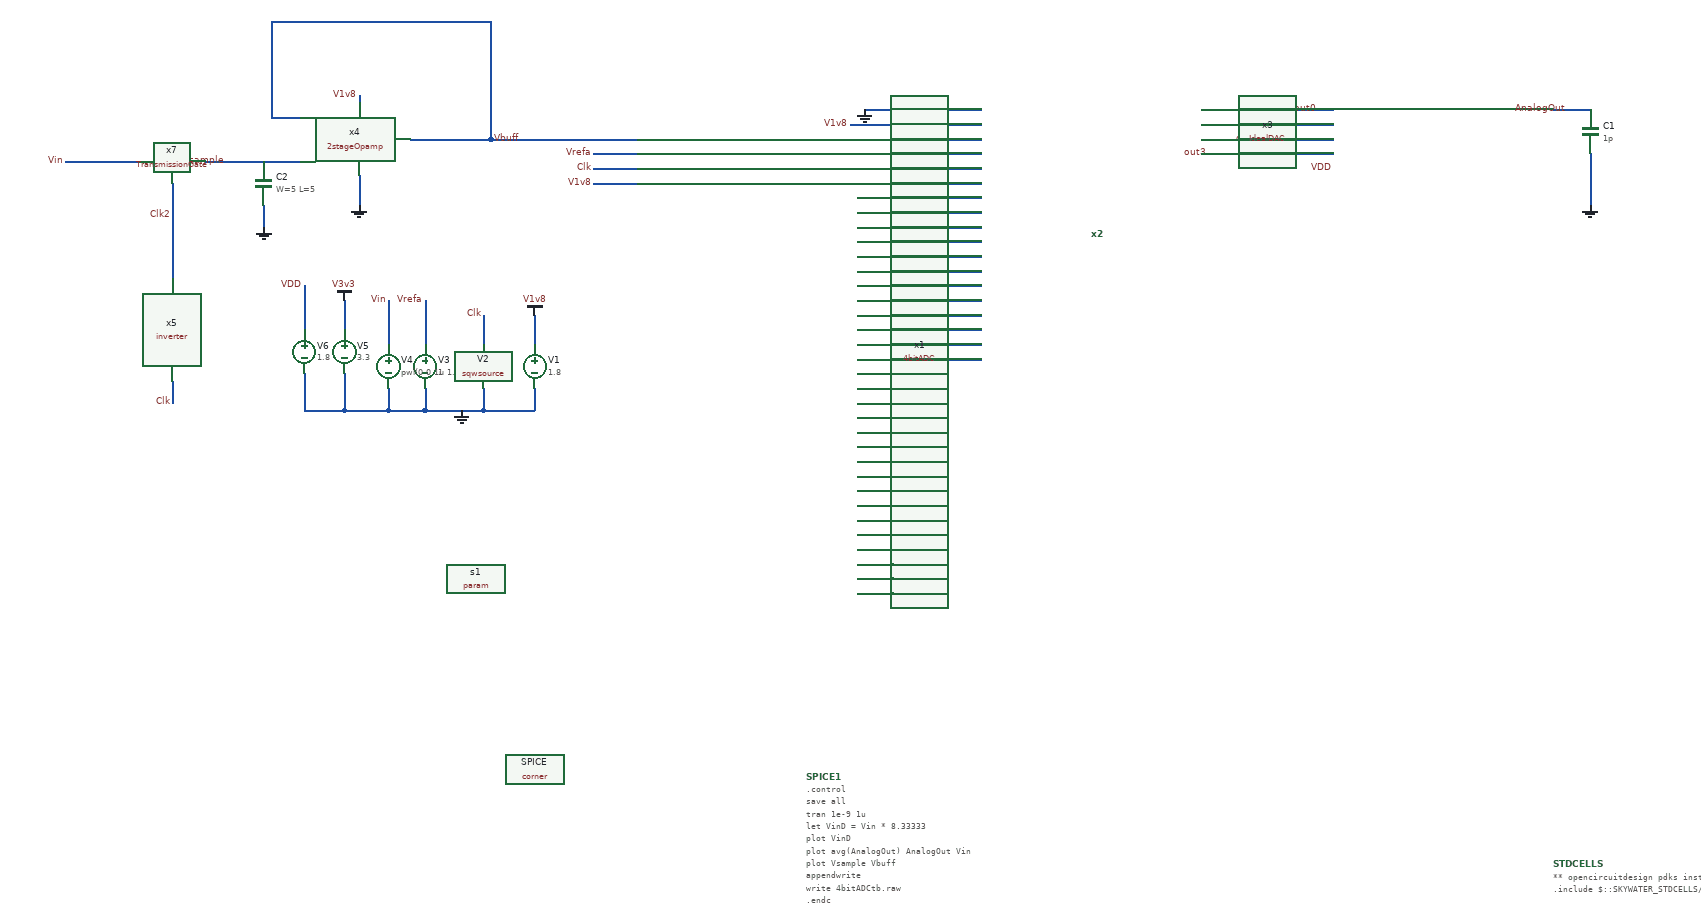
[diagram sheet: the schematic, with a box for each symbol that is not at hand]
v {xschem version=3.4.4 file_version=1.2
}
G {}
K {}
V {}
S {}
E {}
B 2 40 -1110 840 -710 {flags=graph
y1=0

ypos1=-0.0455644
ypos2=1.28959
divy=5
subdivy=5
unity=1
x1=0
x2=1e-06
divx=5
subdivx=5

ylabmag=1.0


dataset=-1
unitx=1
logx=0
logy=0
digital=1


color=4
node=BUS_NAME,x2.xoutput19.a_109_47#,x2.xoutput18.a_109_47#,x2.xoutput17.a_109_47#,x2.xoutput16.a_109_47#
xlabmag=1
y2=1.8}
N -1190 -300 -1190 -240 {
lab=Vrefa}
N -1240 -300 -1240 -240 {
lab=Vin}
N -1040 -280 -1040 -240 {
lab=V1v8}
N -1110 -280 -1110 -240 {
lab=Clk}
N -1240 -180 -1240 -150 {
lab=GND}
N -1110 -150 -1040 -150 {
lab=GND}
N -1040 -180 -1040 -150 {
lab=GND}
N -1190 -180 -1190 -150 {
lab=GND}
N -1110 -180 -1110 -150 {
lab=GND}
N -960 -460 -900 -460 {
lab=V1v8}
N -960 -480 -900 -480 {
lab=Clk}
N -960 -500 -900 -500 {
lab=Vrefa}
N -960 -520 -900 -520 {
lab=Vbuff}
N -1240 -150 -1190 -150 {
lab=GND}
N -1190 -150 -1110 -150 {
lab=GND}
N -130 -560 50 -560 {
lab=out0}
N -130 -540 -10 -540 {
lab=out1}
N -130 -520 -60 -520 {
lab=out2}
N -130 -500 -110 -500 {
lab=out3}
N -595 -200 -560 -200 {
lab=#net1}
N -600 -200 -595 -200 {
lab=#net1}
N -600 -180 -560 -180 {
lab=#net2}
N -600 -160 -560 -160 {
lab=#net3}
N -600 -140 -560 -140 {
lab=#net4}
N -600 -120 -560 -120 {
lab=#net5}
N -600 -100 -560 -100 {
lab=#net6}
N -595 -80 -560 -80 {
lab=#net7}
N -600 -80 -595 -80 {
lab=#net7}
N -600 -60 -555 -60 {
lab=#net8}
N -600 -40 -560 -40 {
lab=#net9}
N -600 -20 -560 -20 {
lab=#net10}
N -600 0 -560 0 {
lab=#net11}
N -600 20 -560 20 {
lab=#net12}
N -600 40 -560 40 {
lab=#net13}
N -600 60 -560 60 {
lab=#net14}
N -600 80 -560 80 {
lab=#net15}
N -600 100 -560 100 {
lab=#net16}
N -580 -540 -430 -540 {
lab=V1v8}
N -610 -540 -580 -540 {
lab=V1v8}
N -590 -560 -430 -560 {
lab=GND}
N -10 -540 50 -540 {
lab=out1}
N -60 -520 50 -520 {
lab=out2}
N -110 -500 50 -500 {
lab=out3}
N -560 60 -550 60 {
lab=#net14}
N -560 80 -550 80 {
lab=#net15}
N -560 100 -550 100 {
lab=#net16}
N -480 -220 -430 -220 {
lab=#net17}
N -480 -240 -430 -240 {
lab=#net18}
N -480 -280 -430 -280 {
lab=#net19}
N -480 -260 -430 -260 {
lab=#net20}
N -480 -300 -430 -300 {
lab=#net21}
N -480 -320 -430 -320 {
lab=#net22}
N -480 -340 -430 -340 {
lab=#net23}
N -480 -360 -430 -360 {
lab=#net24}
N -480 -380 -430 -380 {
lab=#net25}
N -480 -400 -430 -400 {
lab=#net26}
N -480 -420 -430 -420 {
lab=#net27}
N -480 -440 -430 -440 {
lab=#net28}
N -480 -460 -430 -460 {
lab=#net29}
N -480 -480 -430 -480 {
lab=#net30}
N -480 -500 -430 -500 {
lab=#net31}
N -480 -520 -430 -520 {
lab=#net32}
N -600 -520 -560 -520 {
lab=#net32}
N -600 -500 -560 -500 {
lab=#net31}
N -600 -480 -560 -480 {
lab=#net30}
N -600 -460 -560 -460 {
lab=#net29}
N -600 -440 -560 -440 {
lab=#net28}
N -600 -400 -560 -400 {
lab=#net26}
N -600 -420 -560 -420 {
lab=#net27}
N -600 -380 -560 -380 {
lab=#net25}
N -600 -360 -560 -360 {
lab=#net24}
N -600 -340 -560 -340 {
lab=#net23}
N -600 -320 -560 -320 {
lab=#net22}
N -600 -300 -560 -300 {
lab=#net21}
N -600 -280 -560 -280 {
lab=#net19}
N -600 -260 -560 -260 {
lab=#net20}
N -600 -240 -560 -240 {
lab=#net18}
N -600 -220 -560 -220 {
lab=#net17}
N -560 -220 -480 -220 {
lab=#net17}
N -560 -240 -480 -240 {
lab=#net18}
N -560 -280 -480 -280 {
lab=#net19}
N -560 -300 -480 -300 {
lab=#net21}
N -560 -320 -480 -320 {
lab=#net22}
N -560 -340 -480 -340 {
lab=#net23}
N -560 -360 -480 -360 {
lab=#net24}
N -560 -380 -480 -380 {
lab=#net25}
N -560 -400 -480 -400 {
lab=#net26}
N -560 -420 -480 -420 {
lab=#net27}
N -560 -440 -480 -440 {
lab=#net28}
N -560 -460 -480 -460 {
lab=#net29}
N -560 -500 -480 -500 {
lab=#net31}
N -560 -480 -480 -480 {
lab=#net30}
N -560 -520 -480 -520 {
lab=#net32}
N -560 -260 -480 -260 {
lab=#net20}
N 350 -560 400 -560 {
lab=AnalogOut}
N 400 -500 400 -430 {
lab=GND}
N -1680 -490 -1580 -490 {
lab=Vin}
N -1410 -430 -1410 -400 {
lab=GND}
N -1410 -490 -1360 -490 {
lab=Vsample}
N -1190 -520 -1100 -520 {
lab=Vbuff}
N -1100 -680 -1100 -520 {
lab=Vbuff}
N -1400 -680 -1100 -680 {
lab=Vbuff}
N -1280 -470 -1280 -430 {
lab=GND}
N -1100 -520 -960 -520 {
lab=Vbuff}
N -1400 -550 -1360 -550 {
lab=Vbuff}
N -1400 -680 -1400 -550 {
lab=Vbuff}
N -1210 -520 -1190 -520 {
lab=Vbuff}
N -1280 -580 -1280 -570 {
lab=V1v8}
N -1535 -190 -1535 -160 {
lab=Clk}
N -1300 -300 -1300 -260 {
lab=V3v3}
N -1300 -200 -1300 -170 {
lab=GND}
N -1300 -170 -1300 -150 {
lab=GND}
N -1300 -150 -1240 -150 {
lab=GND}
N -1535 -460 -1535 -420 {
lab=Clk2}
N -1535 -420 -1535 -400 {
lab=Clk2}
N -1535 -400 -1535 -330 {
lab=Clk2}
N -1490 -490 -1460 -490 {
lab=Vsample}
N -1460 -490 -1410 -490 {
lab=Vsample}
N -1355 -320 -1355 -260 {
lab=VDD}
N -1355 -200 -1355 -170 {
lab=GND}
N -1355 -170 -1355 -150 {
lab=GND}
N -1355 -150 -1305 -150 {
lab=GND}
N -1305 -150 -1300 -150 {
lab=GND}
C {devices/lab_pin.sym} -1110 -280 1 0 {name=p6 lab=Clk}
C {sky130_fd_pr/corner.sym} -1040 340 0 0 {name=SPICE only_toplevel=true corner=tt}
C {devices/vsource.sym} -1040 -210 0 0 {name=V1 value=1.8 savecurrent=false}
C {devices/vsource.sym} -1190 -210 0 0 {name=V3 value=1 savecurrent=true
}
C {devices/lab_pin.sym} -1190 -300 1 0 {name=p44 sig_type=std_logic lab=Vrefa}
C {devices/vsource.sym} -1240 -210 0 0 {name=V4 value="pwl(0 0 1u 1.1)" savecurrent=true}
C {devices/gnd.sym} -1140 -150 0 1 {name=l10 lab=GND}
C {devices/launcher.sym} -1530 150 0 0 {name=h15
descr="Annotate OP" 
tclcommand="set show_hidden_texts 1; xschem annotate_op"
}
C {devices/launcher.sym} -1520 200 0 0 {name=h3
descr="Netlist & sim" 
tclcommand="xschem netlist; xschem simulate"}
C {devices/code_shown.sym} -670 350 0 0 {name=SPICE1
only_toplevel=false 
value="
.control
save all

tran 1e-9 1u

let VinD = Vin * 8.33333
plot VinD

plot avg(AnalogOut) AnalogOut Vin
plot Vsample Vbuff

appendwrite
write 4bitADCtb.raw
.endc
"}
C {devices/lab_pin.sym} -960 -500 0 0 {name=p9 sig_type=std_logic lab=Vrefa}
C {devices/lab_pin.sym} -960 -480 0 0 {name=p10 lab=Clk}
C {devices/param.sym} -1120 80 0 0 {name=s1 value="r=1"}
C {devices/sqwsource.sym} -1110 -210 0 0 {name=V2 vhi=1.8 freq=60e6}
C {devices/launcher.sym} 900 -730 0 0 {name=h5
descr="load waves" 
tclcommand="xschem raw_read $netlist_dir/4bitADCtb.raw tran"
}
C {devices/lab_pin.sym} -960 -460 2 1 {name=p1 sig_type=std_logic lab=V1v8}
C {devices/gnd.sym} -590 -560 1 0 {name=l1 lab=GND}
C {devices/lab_pin.sym} 30 -560 1 0 {name=p2 sig_type=std_logic lab=out0}
C {devices/lab_pin.sym} -120 -500 1 0 {name=p7 sig_type=std_logic lab=out3}
C {devices/lab_pin.sym} -1680 -490 0 0 {name=p12 lab=Vin
}
C {xschem/userLib/Priority_Encoder_16t4.sym} -280 -390 0 0 {name=x2 prefix=sky130_fd_sc_hd__ }
C {devices/code.sym} 350 470 0 0 {name=STDCELLS
only_toplevel=false
format="tcleval( @value )"
value="
** opencircuitdesign pdks install
.include $::SKYWATER_STDCELLS/sky130_fd_sc_hd.spice

"
spice_ignore=false}
C {devices/lab_pin.sym} -20 -540 1 0 {name=p3 sig_type=std_logic lab=out1}
C {devices/lab_pin.sym} -50 -520 1 0 {name=p4 sig_type=std_logic lab=out2}
C {xschem/IdealDAC.sym} 200 -520 0 0 {name=x3}
C {devices/lab_pin.sym} 50 -480 2 1 {name=p5 sig_type=std_logic lab=VDD}
C {devices/capa.sym} 400 -530 0 0 {name=C1
m=1
value=1p
footprint=1206
device="ceramic capacitor"}
C {devices/gnd.sym} 400 -430 0 0 {name=l2 lab=GND}
C {devices/lab_pin.sym} 370 -560 1 0 {name=p13 sig_type=std_logic lab=AnalogOut}
C {xschem/userLib/4bitADC.sym} -750 -210 0 0 {name=x1}
C {devices/lab_pin.sym} -1535 -160 3 0 {name=p14 lab=Clk}
C {devices/gnd.sym} -1410 -400 0 1 {name=l4 lab=GND}
C {devices/lab_pin.sym} -1280 -580 3 1 {name=p15 sig_type=std_logic lab=V1v8}
C {devices/gnd.sym} -1280 -430 0 1 {name=l5 lab=GND}
C {devices/lab_pin.sym} -1060 -520 1 0 {name=p16 sig_type=std_logic lab=Vbuff}
C {xschem/userLib/inverter.sym} -1535 -250 3 0 {name=x5}
C {devices/vsource.sym} -1300 -230 0 0 {name=V5 value=3.3 savecurrent=false}
C {devices/lab_pin.sym} -1460 -490 1 0 {name=p19 sig_type=std_logic lab=Vsample}
C {devices/lab_pin.sym} -1535 -415 0 0 {name=p20 sig_type=std_logic lab=Clk2}
C {xschem/userLib/2stageOpamp.sym} -1290 -510 0 0 {name=x4}
C {xschem/TransmissionGate.sym} -1480 -490 2 1 {name=x7}
C {devices/vsource.sym} -1355 -230 0 0 {name=V6 value=1.8 savecurrent=true}
C {devices/lab_pin.sym} -1355 -320 1 0 {name=p17 lab=VDD
}
C {devices/lab_pin.sym} -1240 -300 1 0 {name=p8 sig_type=std_logic lab=Vin}
C {devices/lab_pin.sym} -610 -540 0 0 {name=p11 sig_type=std_logic lab=V1v8}
C {devices/vdd.sym} -1040 -280 0 0 {name=l3 lab=V1v8}
C {devices/vdd.sym} -1300 -300 0 0 {name=l6 lab=V3v3}
C {dependencies/pdks/sky130B/libs.tech/xschem/sky130_fd_pr/cap_mim_m3_2.sym} -1410 -460 0 0 {name=C2 model=cap_mim_m3_2 W=5 L=5 MF=10 spiceprefix=X}
